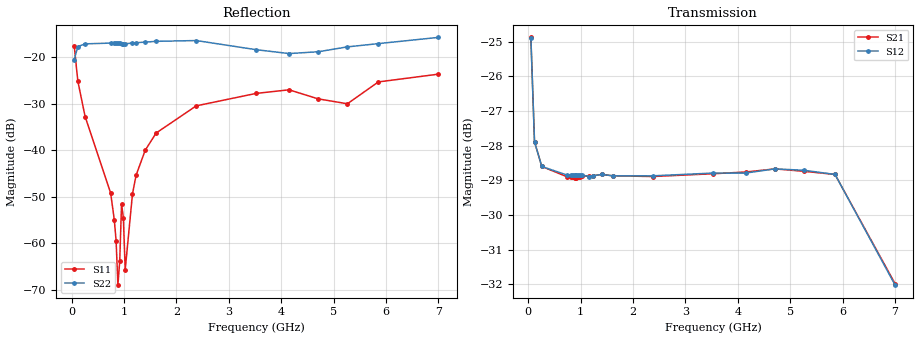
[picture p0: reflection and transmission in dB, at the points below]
! Integrated Device Technology
! Corporate Headquarters
! 6024 Silver Creek Valley Road
! San Jose, CA 95138  USA
! Phone:  1-408-284-8200
! Toll Free:  1-800-223-1366
! Webpage:  http://www.idt.com/
! Timing and RF Division
! 515 Groton Road, Suite 102
! Westford, MA 01886-6024
! Device:  F2258
! Description: Voltage Variable RF Attenuator
! Frequency:  50.0 -  6000.00 MHz
! Package:  3x3 mm Thin QFN Plastic Package: 16 pin
! Ports:  2 RF, 2 DC
!  Pin  1  = NC
!  Pin  2  = NC
!  Pin  3  = RF2  = Port 2
!  Pin  4  = GND
!  Pin  5  = Vdd
!  Pin  6  = NC
!  Pin  7  = VCTRL
!  Pin  8  = NC
!  Pin  9  = GND
!  Pin 10  = RF1  = Port 1
!  Pin 11  = NC
!  Pin 12  = NC
!  Pin 13  = NC
!  Pin 14  = NC
!  Pin 15  = NC
!  Pin 16  = NC
! Vcntrl:  1.630 Volts
! Vdd:  +3.300 Volts
! Current:  1.161 mA
! Data:  The device was measured on a the F2258 evaluation board which has
!  individual transmission lines to the RF pins.  Data was collected
!  using a calibrated network analyzer.  The evaluation board was
!  de-embedded using a TRL calibration technique.
!  The reference plane is the edge of the package pin.
! Misc:  SN 10
!  Action Tracker AT0285
! Date Measured:  2014-12-10
! Date:  2016-01-13  MJV
! Note:
!  Integrated Device Technology supplies this data as a sample of measured
!  data at the package pin for this product.  Your particular data for this
!  product may vary.
!  Data was taken at 25 degrees C.
!  Integrated Device Technology reserves the right to change this data at anytime.
!Freq_(GHz)  S11M_(dB)  S11P_(deg)  S21M_(dB)  S21P_(deg)  S12M_(dB)  S12P_(deg)  S22M_(dB)  S22P_(deg)
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# GHz S dB R 50
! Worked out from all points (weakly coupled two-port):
!   201 points, 50 MHz to 7 GHz, reference 50 ohm
!   highest |S21| = -24.88 dB at 50 MHz (marker M1); lowest = -32.0 dB at 7 GHz (marker M2)
!   lowest |S11| = -69.0 dB at 884 MHz (marker M3), VSWR 1.00, Z = 50 + j0.00357 ohm
!   |S11| at or under -10 dB: start of sweep to end of sweep
!   |S22| runs from -20.5 to -15.7 dB; largest |S21 - S12| = 0.00036
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0.05  -17.53 -109.7  -24.88 -48.2  -24.89 -48.2  -20.51 -35.3
0.1195  -25.14 -104.5  -27.89 -25.9  -27.89 -25.9  -17.69 -10.5
0.2585  -32.76 -106.5  -28.60 -14.5  -28.60 -14.5  -17.10 -6.8
0.745  -49.18 -114.7  -28.90 -11.0  -28.85 -11.0  -16.94 -10.6
0.8145  -54.91 -117.8  -28.90 -11.2  -28.84 -11.2  -16.95 -11.4
0.84925  -59.42 -125.8  -28.89 -11.3  -28.85 -11.3  -16.97 -12.0
0.884  -69.00 174.2  -28.92 -11.4  -28.86 -11.5  -16.98 -12.6
0.91875  -63.81 99.9  -28.92 -11.6  -28.84 -11.6  -16.98 -13.2
0.9535  -51.51 -136.1  -28.90 -11.8  -28.85 -11.8  -17.16 -12.8
0.98825  -54.53 -147.9  -28.89 -11.9  -28.85 -11.9  -17.14 -13.6
1.023  -65.71 -131.5  -28.87 -12.1  -28.85 -12.1  -17.08 -14.1
1.162  -49.37 30.9  -28.88 -12.8  -28.89 -12.8  -16.93 -15.7
1.2315  -45.34 25.4  -28.87 -13.3  -28.87 -13.3  -16.85 -16.5
1.40525  -39.98 23.6  -28.83 -14.8  -28.83 -14.8  -16.73 -18.3
1.61375  -36.28 26.1  -28.87 -16.6  -28.87 -16.6  -16.56 -21.0
2.37825  -30.44 44.1  -28.89 -23.0  -28.87 -23.0  -16.39 -29.3
3.525  -27.75 89.8  -28.81 -33.5  -28.79 -33.5  -18.36 -48.3
4.1505  -26.99 104.2  -28.76 -39.7  -28.79 -39.6  -19.19 -65.1
4.7065  -28.94 94.5  -28.67 -45.4  -28.67 -45.4  -18.80 -75.3
5.2625  -29.99 51.5  -28.74 -51.6  -28.71 -51.6  -17.75 -78.5
5.85325  -25.29 28.0  -28.83 -60.0  -28.83 -60.0  -17.05 -78.9
7  -23.62 83.7  -31.98 -72.9  -32.02 -72.8  -15.71 -134.2
